VERSION 5.7 ;
  NOWIREEXTENSIONATPIN ON ;
  DIVIDERCHAR "/" ;
  BUSBITCHARS "[]" ;
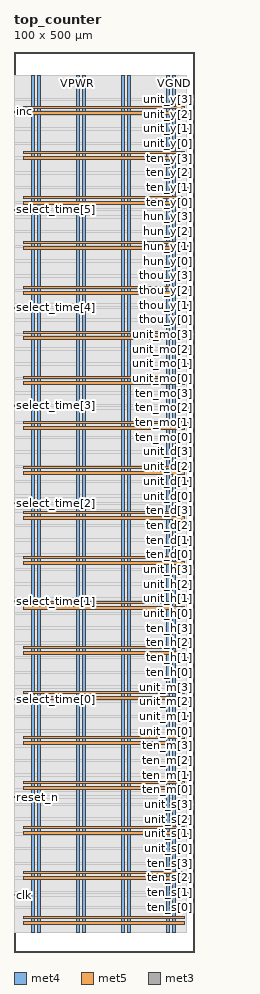
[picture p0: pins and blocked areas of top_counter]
MACRO top_counter
  CLASS BLOCK ;
  FOREIGN top_counter ;
  ORIGIN 0.000 0.000 ;
  SIZE 100.000 BY 500.000 ;
  PIN VGND
    DIRECTION INOUT ;
    USE GROUND ;
    PORT
      LAYER met4 ;
        RECT 13.020 10.640 14.620 487.120 ;
    END
    PORT
      LAYER met4 ;
        RECT 38.020 10.640 39.620 487.120 ;
    END
    PORT
      LAYER met4 ;
        RECT 63.020 10.640 64.620 487.120 ;
    END
    PORT
      LAYER met4 ;
        RECT 88.020 10.640 89.620 487.120 ;
    END
    PORT
      LAYER met5 ;
        RECT 5.280 18.380 94.540 19.980 ;
    END
    PORT
      LAYER met5 ;
        RECT 5.280 43.380 94.540 44.980 ;
    END
    PORT
      LAYER met5 ;
        RECT 5.280 68.380 94.540 69.980 ;
    END
    PORT
      LAYER met5 ;
        RECT 5.280 93.380 94.540 94.980 ;
    END
    PORT
      LAYER met5 ;
        RECT 5.280 118.380 94.540 119.980 ;
    END
    PORT
      LAYER met5 ;
        RECT 5.280 143.380 94.540 144.980 ;
    END
    PORT
      LAYER met5 ;
        RECT 5.280 168.380 94.540 169.980 ;
    END
    PORT
      LAYER met5 ;
        RECT 5.280 193.380 94.540 194.980 ;
    END
    PORT
      LAYER met5 ;
        RECT 5.280 218.380 94.540 219.980 ;
    END
    PORT
      LAYER met5 ;
        RECT 5.280 243.380 94.540 244.980 ;
    END
    PORT
      LAYER met5 ;
        RECT 5.280 268.380 94.540 269.980 ;
    END
    PORT
      LAYER met5 ;
        RECT 5.280 293.380 94.540 294.980 ;
    END
    PORT
      LAYER met5 ;
        RECT 5.280 318.380 94.540 319.980 ;
    END
    PORT
      LAYER met5 ;
        RECT 5.280 343.380 94.540 344.980 ;
    END
    PORT
      LAYER met5 ;
        RECT 5.280 368.380 94.540 369.980 ;
    END
    PORT
      LAYER met5 ;
        RECT 5.280 393.380 94.540 394.980 ;
    END
    PORT
      LAYER met5 ;
        RECT 5.280 418.380 94.540 419.980 ;
    END
    PORT
      LAYER met5 ;
        RECT 5.280 443.380 94.540 444.980 ;
    END
    PORT
      LAYER met5 ;
        RECT 5.280 468.380 94.540 469.980 ;
    END
  END VGND
  PIN VPWR
    DIRECTION INOUT ;
    USE POWER ;
    PORT
      LAYER met4 ;
        RECT 9.720 10.640 11.320 487.120 ;
    END
    PORT
      LAYER met4 ;
        RECT 34.720 10.640 36.320 487.120 ;
    END
    PORT
      LAYER met4 ;
        RECT 59.720 10.640 61.320 487.120 ;
    END
    PORT
      LAYER met4 ;
        RECT 84.720 10.640 86.320 487.120 ;
    END
    PORT
      LAYER met5 ;
        RECT 5.280 15.080 94.540 16.680 ;
    END
    PORT
      LAYER met5 ;
        RECT 5.280 40.080 94.540 41.680 ;
    END
    PORT
      LAYER met5 ;
        RECT 5.280 65.080 94.540 66.680 ;
    END
    PORT
      LAYER met5 ;
        RECT 5.280 90.080 94.540 91.680 ;
    END
    PORT
      LAYER met5 ;
        RECT 5.280 115.080 94.540 116.680 ;
    END
    PORT
      LAYER met5 ;
        RECT 5.280 140.080 94.540 141.680 ;
    END
    PORT
      LAYER met5 ;
        RECT 5.280 165.080 94.540 166.680 ;
    END
    PORT
      LAYER met5 ;
        RECT 5.280 190.080 94.540 191.680 ;
    END
    PORT
      LAYER met5 ;
        RECT 5.280 215.080 94.540 216.680 ;
    END
    PORT
      LAYER met5 ;
        RECT 5.280 240.080 94.540 241.680 ;
    END
    PORT
      LAYER met5 ;
        RECT 5.280 265.080 94.540 266.680 ;
    END
    PORT
      LAYER met5 ;
        RECT 5.280 290.080 94.540 291.680 ;
    END
    PORT
      LAYER met5 ;
        RECT 5.280 315.080 94.540 316.680 ;
    END
    PORT
      LAYER met5 ;
        RECT 5.280 340.080 94.540 341.680 ;
    END
    PORT
      LAYER met5 ;
        RECT 5.280 365.080 94.540 366.680 ;
    END
    PORT
      LAYER met5 ;
        RECT 5.280 390.080 94.540 391.680 ;
    END
    PORT
      LAYER met5 ;
        RECT 5.280 415.080 94.540 416.680 ;
    END
    PORT
      LAYER met5 ;
        RECT 5.280 440.080 94.540 441.680 ;
    END
    PORT
      LAYER met5 ;
        RECT 5.280 465.080 94.540 466.680 ;
    END
  END VPWR
  PIN clk
    DIRECTION INPUT ;
    USE SIGNAL ;
    ANTENNAGATEAREA 0.852000 ;
    PORT
      LAYER met3 ;
        RECT 0.000 31.320 4.000 31.920 ;
    END
  END clk
  PIN hun_y[0]
    DIRECTION OUTPUT ;
    USE SIGNAL ;
    ANTENNADIFFAREA 0.445500 ;
    PORT
      LAYER met3 ;
        RECT 96.000 383.560 100.000 384.160 ;
    END
  END hun_y[0]
  PIN hun_y[1]
    DIRECTION OUTPUT ;
    USE SIGNAL ;
    ANTENNADIFFAREA 0.445500 ;
    PORT
      LAYER met3 ;
        RECT 96.000 391.720 100.000 392.320 ;
    END
  END hun_y[1]
  PIN hun_y[2]
    DIRECTION OUTPUT ;
    USE SIGNAL ;
    ANTENNADIFFAREA 0.445500 ;
    PORT
      LAYER met3 ;
        RECT 96.000 399.880 100.000 400.480 ;
    END
  END hun_y[2]
  PIN hun_y[3]
    DIRECTION OUTPUT ;
    USE SIGNAL ;
    ANTENNADIFFAREA 0.445500 ;
    PORT
      LAYER met3 ;
        RECT 96.000 408.040 100.000 408.640 ;
    END
  END hun_y[3]
  PIN inc
    DIRECTION INPUT ;
    USE SIGNAL ;
    ANTENNAGATEAREA 0.247500 ;
    PORT
      LAYER met3 ;
        RECT 0.000 466.520 4.000 467.120 ;
    END
  END inc
  PIN reset_n
    DIRECTION INPUT ;
    USE SIGNAL ;
    ANTENNAGATEAREA 0.196500 ;
    PORT
      LAYER met3 ;
        RECT 0.000 85.720 4.000 86.320 ;
    END
  END reset_n
  PIN select_time[0]
    DIRECTION INPUT ;
    USE SIGNAL ;
    ANTENNAGATEAREA 0.196500 ;
    PORT
      LAYER met3 ;
        RECT 0.000 140.120 4.000 140.720 ;
    END
  END select_time[0]
  PIN select_time[1]
    DIRECTION INPUT ;
    USE SIGNAL ;
    ANTENNAGATEAREA 0.126000 ;
    PORT
      LAYER met3 ;
        RECT 0.000 194.520 4.000 195.120 ;
    END
  END select_time[1]
  PIN select_time[2]
    DIRECTION INPUT ;
    USE SIGNAL ;
    ANTENNAGATEAREA 0.126000 ;
    PORT
      LAYER met3 ;
        RECT 0.000 248.920 4.000 249.520 ;
    END
  END select_time[2]
  PIN select_time[3]
    DIRECTION INPUT ;
    USE SIGNAL ;
    ANTENNAGATEAREA 0.196500 ;
    PORT
      LAYER met3 ;
        RECT 0.000 303.320 4.000 303.920 ;
    END
  END select_time[3]
  PIN select_time[4]
    DIRECTION INPUT ;
    USE SIGNAL ;
    ANTENNAGATEAREA 0.126000 ;
    PORT
      LAYER met3 ;
        RECT 0.000 357.720 4.000 358.320 ;
    END
  END select_time[4]
  PIN select_time[5]
    DIRECTION INPUT ;
    USE SIGNAL ;
    ANTENNAGATEAREA 0.213000 ;
    PORT
      LAYER met3 ;
        RECT 0.000 412.120 4.000 412.720 ;
    END
  END select_time[5]
  PIN ten_d[0]
    DIRECTION OUTPUT ;
    USE SIGNAL ;
    ANTENNADIFFAREA 0.445500 ;
    PORT
      LAYER met3 ;
        RECT 96.000 220.360 100.000 220.960 ;
    END
  END ten_d[0]
  PIN ten_d[1]
    DIRECTION OUTPUT ;
    USE SIGNAL ;
    ANTENNADIFFAREA 0.445500 ;
    PORT
      LAYER met3 ;
        RECT 96.000 228.520 100.000 229.120 ;
    END
  END ten_d[1]
  PIN ten_d[2]
    DIRECTION OUTPUT ;
    USE SIGNAL ;
    ANTENNADIFFAREA 0.445500 ;
    PORT
      LAYER met3 ;
        RECT 96.000 236.680 100.000 237.280 ;
    END
  END ten_d[2]
  PIN ten_d[3]
    DIRECTION OUTPUT ;
    USE SIGNAL ;
    ANTENNADIFFAREA 0.445500 ;
    PORT
      LAYER met3 ;
        RECT 96.000 244.840 100.000 245.440 ;
    END
  END ten_d[3]
  PIN ten_h[0]
    DIRECTION OUTPUT ;
    USE SIGNAL ;
    ANTENNADIFFAREA 0.445500 ;
    PORT
      LAYER met3 ;
        RECT 96.000 155.080 100.000 155.680 ;
    END
  END ten_h[0]
  PIN ten_h[1]
    DIRECTION OUTPUT ;
    USE SIGNAL ;
    ANTENNADIFFAREA 0.445500 ;
    PORT
      LAYER met3 ;
        RECT 96.000 163.240 100.000 163.840 ;
    END
  END ten_h[1]
  PIN ten_h[2]
    DIRECTION OUTPUT ;
    USE SIGNAL ;
    ANTENNADIFFAREA 0.445500 ;
    PORT
      LAYER met3 ;
        RECT 96.000 171.400 100.000 172.000 ;
    END
  END ten_h[2]
  PIN ten_h[3]
    DIRECTION OUTPUT ;
    USE SIGNAL ;
    ANTENNADIFFAREA 0.445500 ;
    PORT
      LAYER met3 ;
        RECT 96.000 179.560 100.000 180.160 ;
    END
  END ten_h[3]
  PIN ten_m[0]
    DIRECTION OUTPUT ;
    USE SIGNAL ;
    ANTENNADIFFAREA 0.445500 ;
    PORT
      LAYER met3 ;
        RECT 96.000 89.800 100.000 90.400 ;
    END
  END ten_m[0]
  PIN ten_m[1]
    DIRECTION OUTPUT ;
    USE SIGNAL ;
    ANTENNADIFFAREA 0.445500 ;
    PORT
      LAYER met3 ;
        RECT 96.000 97.960 100.000 98.560 ;
    END
  END ten_m[1]
  PIN ten_m[2]
    DIRECTION OUTPUT ;
    USE SIGNAL ;
    ANTENNADIFFAREA 0.445500 ;
    PORT
      LAYER met3 ;
        RECT 96.000 106.120 100.000 106.720 ;
    END
  END ten_m[2]
  PIN ten_m[3]
    DIRECTION OUTPUT ;
    USE SIGNAL ;
    PORT
      LAYER met3 ;
        RECT 96.000 114.280 100.000 114.880 ;
    END
  END ten_m[3]
  PIN ten_mo[0]
    DIRECTION OUTPUT ;
    USE SIGNAL ;
    ANTENNADIFFAREA 0.445500 ;
    PORT
      LAYER met3 ;
        RECT 96.000 285.640 100.000 286.240 ;
    END
  END ten_mo[0]
  PIN ten_mo[1]
    DIRECTION OUTPUT ;
    USE SIGNAL ;
    ANTENNADIFFAREA 0.445500 ;
    PORT
      LAYER met3 ;
        RECT 96.000 293.800 100.000 294.400 ;
    END
  END ten_mo[1]
  PIN ten_mo[2]
    DIRECTION OUTPUT ;
    USE SIGNAL ;
    ANTENNADIFFAREA 0.445500 ;
    PORT
      LAYER met3 ;
        RECT 96.000 301.960 100.000 302.560 ;
    END
  END ten_mo[2]
  PIN ten_mo[3]
    DIRECTION OUTPUT ;
    USE SIGNAL ;
    ANTENNADIFFAREA 0.445500 ;
    PORT
      LAYER met3 ;
        RECT 96.000 310.120 100.000 310.720 ;
    END
  END ten_mo[3]
  PIN ten_s[0]
    DIRECTION OUTPUT ;
    USE SIGNAL ;
    ANTENNADIFFAREA 0.445500 ;
    PORT
      LAYER met3 ;
        RECT 96.000 24.520 100.000 25.120 ;
    END
  END ten_s[0]
  PIN ten_s[1]
    DIRECTION OUTPUT ;
    USE SIGNAL ;
    ANTENNADIFFAREA 0.445500 ;
    PORT
      LAYER met3 ;
        RECT 96.000 32.680 100.000 33.280 ;
    END
  END ten_s[1]
  PIN ten_s[2]
    DIRECTION OUTPUT ;
    USE SIGNAL ;
    ANTENNADIFFAREA 0.445500 ;
    PORT
      LAYER met3 ;
        RECT 96.000 40.840 100.000 41.440 ;
    END
  END ten_s[2]
  PIN ten_s[3]
    DIRECTION OUTPUT ;
    USE SIGNAL ;
    ANTENNADIFFAREA 0.445500 ;
    PORT
      LAYER met3 ;
        RECT 96.000 49.000 100.000 49.600 ;
    END
  END ten_s[3]
  PIN ten_y[0]
    DIRECTION OUTPUT ;
    USE SIGNAL ;
    ANTENNADIFFAREA 0.445500 ;
    PORT
      LAYER met3 ;
        RECT 96.000 416.200 100.000 416.800 ;
    END
  END ten_y[0]
  PIN ten_y[1]
    DIRECTION OUTPUT ;
    USE SIGNAL ;
    ANTENNADIFFAREA 0.445500 ;
    PORT
      LAYER met3 ;
        RECT 96.000 424.360 100.000 424.960 ;
    END
  END ten_y[1]
  PIN ten_y[2]
    DIRECTION OUTPUT ;
    USE SIGNAL ;
    ANTENNADIFFAREA 0.445500 ;
    PORT
      LAYER met3 ;
        RECT 96.000 432.520 100.000 433.120 ;
    END
  END ten_y[2]
  PIN ten_y[3]
    DIRECTION OUTPUT ;
    USE SIGNAL ;
    ANTENNADIFFAREA 0.445500 ;
    PORT
      LAYER met3 ;
        RECT 96.000 440.680 100.000 441.280 ;
    END
  END ten_y[3]
  PIN thou_y[0]
    DIRECTION OUTPUT ;
    USE SIGNAL ;
    PORT
      LAYER met3 ;
        RECT 96.000 350.920 100.000 351.520 ;
    END
  END thou_y[0]
  PIN thou_y[1]
    DIRECTION OUTPUT ;
    USE SIGNAL ;
    PORT
      LAYER met3 ;
        RECT 96.000 359.080 100.000 359.680 ;
    END
  END thou_y[1]
  PIN thou_y[2]
    DIRECTION OUTPUT ;
    USE SIGNAL ;
    PORT
      LAYER met3 ;
        RECT 96.000 367.240 100.000 367.840 ;
    END
  END thou_y[2]
  PIN thou_y[3]
    DIRECTION OUTPUT ;
    USE SIGNAL ;
    PORT
      LAYER met3 ;
        RECT 96.000 375.400 100.000 376.000 ;
    END
  END thou_y[3]
  PIN unit_d[0]
    DIRECTION OUTPUT ;
    USE SIGNAL ;
    ANTENNADIFFAREA 0.445500 ;
    PORT
      LAYER met3 ;
        RECT 96.000 253.000 100.000 253.600 ;
    END
  END unit_d[0]
  PIN unit_d[1]
    DIRECTION OUTPUT ;
    USE SIGNAL ;
    ANTENNADIFFAREA 0.445500 ;
    PORT
      LAYER met3 ;
        RECT 96.000 261.160 100.000 261.760 ;
    END
  END unit_d[1]
  PIN unit_d[2]
    DIRECTION OUTPUT ;
    USE SIGNAL ;
    ANTENNADIFFAREA 0.445500 ;
    PORT
      LAYER met3 ;
        RECT 96.000 269.320 100.000 269.920 ;
    END
  END unit_d[2]
  PIN unit_d[3]
    DIRECTION OUTPUT ;
    USE SIGNAL ;
    ANTENNADIFFAREA 0.445500 ;
    PORT
      LAYER met3 ;
        RECT 96.000 277.480 100.000 278.080 ;
    END
  END unit_d[3]
  PIN unit_h[0]
    DIRECTION OUTPUT ;
    USE SIGNAL ;
    ANTENNADIFFAREA 0.445500 ;
    PORT
      LAYER met3 ;
        RECT 96.000 187.720 100.000 188.320 ;
    END
  END unit_h[0]
  PIN unit_h[1]
    DIRECTION OUTPUT ;
    USE SIGNAL ;
    ANTENNADIFFAREA 0.445500 ;
    PORT
      LAYER met3 ;
        RECT 96.000 195.880 100.000 196.480 ;
    END
  END unit_h[1]
  PIN unit_h[2]
    DIRECTION OUTPUT ;
    USE SIGNAL ;
    ANTENNADIFFAREA 0.445500 ;
    PORT
      LAYER met3 ;
        RECT 96.000 204.040 100.000 204.640 ;
    END
  END unit_h[2]
  PIN unit_h[3]
    DIRECTION OUTPUT ;
    USE SIGNAL ;
    ANTENNADIFFAREA 0.445500 ;
    PORT
      LAYER met3 ;
        RECT 96.000 212.200 100.000 212.800 ;
    END
  END unit_h[3]
  PIN unit_m[0]
    DIRECTION OUTPUT ;
    USE SIGNAL ;
    ANTENNADIFFAREA 0.445500 ;
    PORT
      LAYER met3 ;
        RECT 96.000 122.440 100.000 123.040 ;
    END
  END unit_m[0]
  PIN unit_m[1]
    DIRECTION OUTPUT ;
    USE SIGNAL ;
    ANTENNADIFFAREA 0.445500 ;
    PORT
      LAYER met3 ;
        RECT 96.000 130.600 100.000 131.200 ;
    END
  END unit_m[1]
  PIN unit_m[2]
    DIRECTION OUTPUT ;
    USE SIGNAL ;
    ANTENNADIFFAREA 0.445500 ;
    PORT
      LAYER met3 ;
        RECT 96.000 138.760 100.000 139.360 ;
    END
  END unit_m[2]
  PIN unit_m[3]
    DIRECTION OUTPUT ;
    USE SIGNAL ;
    ANTENNADIFFAREA 0.445500 ;
    PORT
      LAYER met3 ;
        RECT 96.000 146.920 100.000 147.520 ;
    END
  END unit_m[3]
  PIN unit_mo[0]
    DIRECTION OUTPUT ;
    USE SIGNAL ;
    ANTENNADIFFAREA 0.445500 ;
    PORT
      LAYER met3 ;
        RECT 96.000 318.280 100.000 318.880 ;
    END
  END unit_mo[0]
  PIN unit_mo[1]
    DIRECTION OUTPUT ;
    USE SIGNAL ;
    ANTENNADIFFAREA 0.445500 ;
    PORT
      LAYER met3 ;
        RECT 96.000 326.440 100.000 327.040 ;
    END
  END unit_mo[1]
  PIN unit_mo[2]
    DIRECTION OUTPUT ;
    USE SIGNAL ;
    ANTENNADIFFAREA 0.445500 ;
    PORT
      LAYER met3 ;
        RECT 96.000 334.600 100.000 335.200 ;
    END
  END unit_mo[2]
  PIN unit_mo[3]
    DIRECTION OUTPUT ;
    USE SIGNAL ;
    ANTENNADIFFAREA 0.445500 ;
    PORT
      LAYER met3 ;
        RECT 96.000 342.760 100.000 343.360 ;
    END
  END unit_mo[3]
  PIN unit_s[0]
    DIRECTION OUTPUT ;
    USE SIGNAL ;
    ANTENNADIFFAREA 0.445500 ;
    PORT
      LAYER met3 ;
        RECT 96.000 57.160 100.000 57.760 ;
    END
  END unit_s[0]
  PIN unit_s[1]
    DIRECTION OUTPUT ;
    USE SIGNAL ;
    ANTENNADIFFAREA 0.445500 ;
    PORT
      LAYER met3 ;
        RECT 96.000 65.320 100.000 65.920 ;
    END
  END unit_s[1]
  PIN unit_s[2]
    DIRECTION OUTPUT ;
    USE SIGNAL ;
    ANTENNADIFFAREA 0.445500 ;
    PORT
      LAYER met3 ;
        RECT 96.000 73.480 100.000 74.080 ;
    END
  END unit_s[2]
  PIN unit_s[3]
    DIRECTION OUTPUT ;
    USE SIGNAL ;
    ANTENNADIFFAREA 0.445500 ;
    PORT
      LAYER met3 ;
        RECT 96.000 81.640 100.000 82.240 ;
    END
  END unit_s[3]
  PIN unit_y[0]
    DIRECTION OUTPUT ;
    USE SIGNAL ;
    ANTENNADIFFAREA 0.445500 ;
    PORT
      LAYER met3 ;
        RECT 96.000 448.840 100.000 449.440 ;
    END
  END unit_y[0]
  PIN unit_y[1]
    DIRECTION OUTPUT ;
    USE SIGNAL ;
    ANTENNADIFFAREA 0.445500 ;
    PORT
      LAYER met3 ;
        RECT 96.000 457.000 100.000 457.600 ;
    END
  END unit_y[1]
  PIN unit_y[2]
    DIRECTION OUTPUT ;
    USE SIGNAL ;
    ANTENNADIFFAREA 0.445500 ;
    PORT
      LAYER met3 ;
        RECT 96.000 465.160 100.000 465.760 ;
    END
  END unit_y[2]
  PIN unit_y[3]
    DIRECTION OUTPUT ;
    USE SIGNAL ;
    ANTENNADIFFAREA 0.445500 ;
    PORT
      LAYER met3 ;
        RECT 96.000 473.320 100.000 473.920 ;
    END
  END unit_y[3]
  OBS
      LAYER nwell ;
        RECT 5.330 10.795 94.490 487.070 ;
      LAYER li1 ;
        RECT 5.520 10.795 94.300 486.965 ;
      LAYER met1 ;
        RECT 0.530 10.640 94.300 487.120 ;
      LAYER met2 ;
        RECT 0.550 10.695 92.830 487.065 ;
      LAYER met3 ;
        RECT 0.525 474.320 96.000 487.045 ;
        RECT 0.525 472.920 95.600 474.320 ;
        RECT 0.525 467.520 96.000 472.920 ;
        RECT 4.400 466.160 96.000 467.520 ;
        RECT 4.400 466.120 95.600 466.160 ;
        RECT 0.525 464.760 95.600 466.120 ;
        RECT 0.525 458.000 96.000 464.760 ;
        RECT 0.525 456.600 95.600 458.000 ;
        RECT 0.525 449.840 96.000 456.600 ;
        RECT 0.525 448.440 95.600 449.840 ;
        RECT 0.525 441.680 96.000 448.440 ;
        RECT 0.525 440.280 95.600 441.680 ;
        RECT 0.525 433.520 96.000 440.280 ;
        RECT 0.525 432.120 95.600 433.520 ;
        RECT 0.525 425.360 96.000 432.120 ;
        RECT 0.525 423.960 95.600 425.360 ;
        RECT 0.525 417.200 96.000 423.960 ;
        RECT 0.525 415.800 95.600 417.200 ;
        RECT 0.525 413.120 96.000 415.800 ;
        RECT 4.400 411.720 96.000 413.120 ;
        RECT 0.525 409.040 96.000 411.720 ;
        RECT 0.525 407.640 95.600 409.040 ;
        RECT 0.525 400.880 96.000 407.640 ;
        RECT 0.525 399.480 95.600 400.880 ;
        RECT 0.525 392.720 96.000 399.480 ;
        RECT 0.525 391.320 95.600 392.720 ;
        RECT 0.525 384.560 96.000 391.320 ;
        RECT 0.525 383.160 95.600 384.560 ;
        RECT 0.525 376.400 96.000 383.160 ;
        RECT 0.525 375.000 95.600 376.400 ;
        RECT 0.525 368.240 96.000 375.000 ;
        RECT 0.525 366.840 95.600 368.240 ;
        RECT 0.525 360.080 96.000 366.840 ;
        RECT 0.525 358.720 95.600 360.080 ;
        RECT 4.400 358.680 95.600 358.720 ;
        RECT 4.400 357.320 96.000 358.680 ;
        RECT 0.525 351.920 96.000 357.320 ;
        RECT 0.525 350.520 95.600 351.920 ;
        RECT 0.525 343.760 96.000 350.520 ;
        RECT 0.525 342.360 95.600 343.760 ;
        RECT 0.525 335.600 96.000 342.360 ;
        RECT 0.525 334.200 95.600 335.600 ;
        RECT 0.525 327.440 96.000 334.200 ;
        RECT 0.525 326.040 95.600 327.440 ;
        RECT 0.525 319.280 96.000 326.040 ;
        RECT 0.525 317.880 95.600 319.280 ;
        RECT 0.525 311.120 96.000 317.880 ;
        RECT 0.525 309.720 95.600 311.120 ;
        RECT 0.525 304.320 96.000 309.720 ;
        RECT 4.400 302.960 96.000 304.320 ;
        RECT 4.400 302.920 95.600 302.960 ;
        RECT 0.525 301.560 95.600 302.920 ;
        RECT 0.525 294.800 96.000 301.560 ;
        RECT 0.525 293.400 95.600 294.800 ;
        RECT 0.525 286.640 96.000 293.400 ;
        RECT 0.525 285.240 95.600 286.640 ;
        RECT 0.525 278.480 96.000 285.240 ;
        RECT 0.525 277.080 95.600 278.480 ;
        RECT 0.525 270.320 96.000 277.080 ;
        RECT 0.525 268.920 95.600 270.320 ;
        RECT 0.525 262.160 96.000 268.920 ;
        RECT 0.525 260.760 95.600 262.160 ;
        RECT 0.525 254.000 96.000 260.760 ;
        RECT 0.525 252.600 95.600 254.000 ;
        RECT 0.525 249.920 96.000 252.600 ;
        RECT 4.400 248.520 96.000 249.920 ;
        RECT 0.525 245.840 96.000 248.520 ;
        RECT 0.525 244.440 95.600 245.840 ;
        RECT 0.525 237.680 96.000 244.440 ;
        RECT 0.525 236.280 95.600 237.680 ;
        RECT 0.525 229.520 96.000 236.280 ;
        RECT 0.525 228.120 95.600 229.520 ;
        RECT 0.525 221.360 96.000 228.120 ;
        RECT 0.525 219.960 95.600 221.360 ;
        RECT 0.525 213.200 96.000 219.960 ;
        RECT 0.525 211.800 95.600 213.200 ;
        RECT 0.525 205.040 96.000 211.800 ;
        RECT 0.525 203.640 95.600 205.040 ;
        RECT 0.525 196.880 96.000 203.640 ;
        RECT 0.525 195.520 95.600 196.880 ;
        RECT 4.400 195.480 95.600 195.520 ;
        RECT 4.400 194.120 96.000 195.480 ;
        RECT 0.525 188.720 96.000 194.120 ;
        RECT 0.525 187.320 95.600 188.720 ;
        RECT 0.525 180.560 96.000 187.320 ;
        RECT 0.525 179.160 95.600 180.560 ;
        RECT 0.525 172.400 96.000 179.160 ;
        RECT 0.525 171.000 95.600 172.400 ;
        RECT 0.525 164.240 96.000 171.000 ;
        RECT 0.525 162.840 95.600 164.240 ;
        RECT 0.525 156.080 96.000 162.840 ;
        RECT 0.525 154.680 95.600 156.080 ;
        RECT 0.525 147.920 96.000 154.680 ;
        RECT 0.525 146.520 95.600 147.920 ;
        RECT 0.525 141.120 96.000 146.520 ;
        RECT 4.400 139.760 96.000 141.120 ;
        RECT 4.400 139.720 95.600 139.760 ;
        RECT 0.525 138.360 95.600 139.720 ;
        RECT 0.525 131.600 96.000 138.360 ;
        RECT 0.525 130.200 95.600 131.600 ;
        RECT 0.525 123.440 96.000 130.200 ;
        RECT 0.525 122.040 95.600 123.440 ;
        RECT 0.525 115.280 96.000 122.040 ;
        RECT 0.525 113.880 95.600 115.280 ;
        RECT 0.525 107.120 96.000 113.880 ;
        RECT 0.525 105.720 95.600 107.120 ;
        RECT 0.525 98.960 96.000 105.720 ;
        RECT 0.525 97.560 95.600 98.960 ;
        RECT 0.525 90.800 96.000 97.560 ;
        RECT 0.525 89.400 95.600 90.800 ;
        RECT 0.525 86.720 96.000 89.400 ;
        RECT 4.400 85.320 96.000 86.720 ;
        RECT 0.525 82.640 96.000 85.320 ;
        RECT 0.525 81.240 95.600 82.640 ;
        RECT 0.525 74.480 96.000 81.240 ;
        RECT 0.525 73.080 95.600 74.480 ;
        RECT 0.525 66.320 96.000 73.080 ;
        RECT 0.525 64.920 95.600 66.320 ;
        RECT 0.525 58.160 96.000 64.920 ;
        RECT 0.525 56.760 95.600 58.160 ;
        RECT 0.525 50.000 96.000 56.760 ;
        RECT 0.525 48.600 95.600 50.000 ;
        RECT 0.525 41.840 96.000 48.600 ;
        RECT 0.525 40.440 95.600 41.840 ;
        RECT 0.525 33.680 96.000 40.440 ;
        RECT 0.525 32.320 95.600 33.680 ;
        RECT 4.400 32.280 95.600 32.320 ;
        RECT 4.400 30.920 96.000 32.280 ;
        RECT 0.525 25.520 96.000 30.920 ;
        RECT 0.525 24.120 95.600 25.520 ;
        RECT 0.525 10.715 96.000 24.120 ;
  END
END top_counter
END LIBRARY

